VERSION 5.7 ;
  NOWIREEXTENSIONATPIN ON ;
  DIVIDERCHAR "/" ;
  BUSBITCHARS "[]" ;
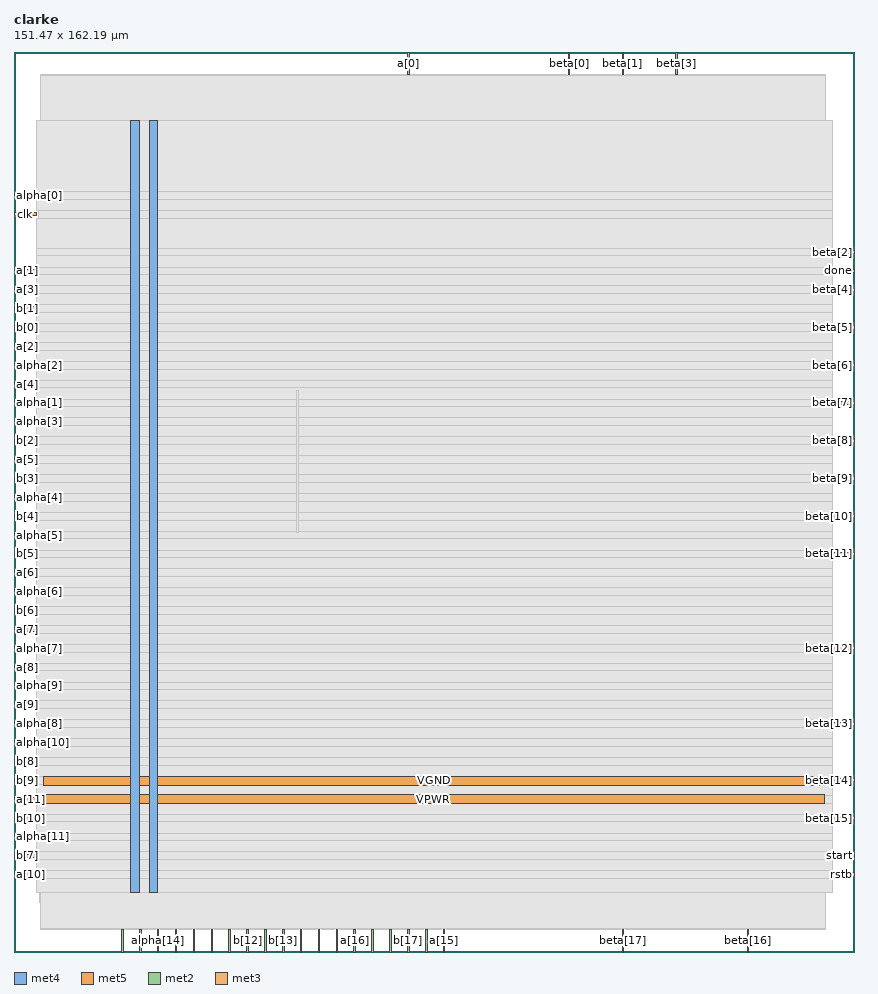
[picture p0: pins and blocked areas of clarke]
MACRO clarke
  CLASS BLOCK ;
  FOREIGN clarke ;
  ORIGIN 0.000 0.000 ;
  SIZE 151.470 BY 162.190 ;
  PIN VGND
    DIRECTION INOUT ;
    USE GROUND ;
    PORT
      LAYER met4 ;
        RECT 24.340 10.640 25.940 149.840 ;
    END
    PORT
      LAYER met5 ;
        RECT 5.280 30.030 146.060 31.630 ;
    END
  END VGND
  PIN VPWR
    DIRECTION INOUT ;
    USE POWER ;
    PORT
      LAYER met4 ;
        RECT 21.040 10.640 22.640 149.840 ;
    END
    PORT
      LAYER met5 ;
        RECT 5.280 26.730 146.060 28.330 ;
    END
  END VPWR
  PIN a[0]
    DIRECTION INPUT ;
    USE SIGNAL ;
    ANTENNAGATEAREA 0.126000 ;
    PORT
      LAYER met2 ;
        RECT 70.930 158.190 71.210 162.190 ;
    END
  END a[0]
  PIN a[10]
    DIRECTION INPUT ;
    USE SIGNAL ;
    ANTENNAGATEAREA 0.196500 ;
    PORT
      LAYER met3 ;
        RECT 0.000 13.640 4.000 14.240 ;
    END
  END a[10]
  PIN a[11]
    DIRECTION INPUT ;
    USE SIGNAL ;
    ANTENNAGATEAREA 0.196500 ;
    PORT
      LAYER met3 ;
        RECT 0.000 27.240 4.000 27.840 ;
    END
  END a[11]
  PIN a[12]
    DIRECTION INPUT ;
    USE SIGNAL ;
    ANTENNAGATEAREA 0.196500 ;
    PORT
      LAYER met2 ;
        RECT 19.410 0.000 19.690 4.000 ;
    END
  END a[12]
  PIN a[13]
    DIRECTION INPUT ;
    USE SIGNAL ;
    ANTENNAGATEAREA 0.196500 ;
    PORT
      LAYER met2 ;
        RECT 32.290 0.000 32.570 4.000 ;
    END
  END a[13]
  PIN a[14]
    DIRECTION INPUT ;
    USE SIGNAL ;
    ANTENNAGATEAREA 0.196500 ;
    PORT
      LAYER met2 ;
        RECT 22.630 0.000 22.910 4.000 ;
    END
  END a[14]
  PIN a[15]
    DIRECTION INPUT ;
    USE SIGNAL ;
    ANTENNAGATEAREA 0.196500 ;
    PORT
      LAYER met2 ;
        RECT 77.370 0.000 77.650 4.000 ;
    END
  END a[15]
  PIN a[16]
    DIRECTION INPUT ;
    USE SIGNAL ;
    ANTENNAGATEAREA 0.196500 ;
    PORT
      LAYER met2 ;
        RECT 61.270 0.000 61.550 4.000 ;
    END
  END a[16]
  PIN a[17]
    DIRECTION INPUT ;
    USE SIGNAL ;
    ANTENNAGATEAREA 0.213000 ;
    PORT
      LAYER met2 ;
        RECT 74.150 0.000 74.430 4.000 ;
    END
  END a[17]
  PIN a[1]
    DIRECTION INPUT ;
    USE SIGNAL ;
    ANTENNAGATEAREA 0.196500 ;
    PORT
      LAYER met3 ;
        RECT 0.000 122.440 4.000 123.040 ;
    END
  END a[1]
  PIN a[2]
    DIRECTION INPUT ;
    USE SIGNAL ;
    ANTENNAGATEAREA 0.495000 ;
    PORT
      LAYER met3 ;
        RECT 0.000 108.840 4.000 109.440 ;
    END
  END a[2]
  PIN a[3]
    DIRECTION INPUT ;
    USE SIGNAL ;
    ANTENNAGATEAREA 0.196500 ;
    PORT
      LAYER met3 ;
        RECT 0.000 119.040 4.000 119.640 ;
    END
  END a[3]
  PIN a[4]
    DIRECTION INPUT ;
    USE SIGNAL ;
    ANTENNAGATEAREA 0.196500 ;
    PORT
      LAYER met3 ;
        RECT 0.000 102.040 4.000 102.640 ;
    END
  END a[4]
  PIN a[5]
    DIRECTION INPUT ;
    USE SIGNAL ;
    ANTENNAGATEAREA 0.196500 ;
    PORT
      LAYER met3 ;
        RECT 0.000 88.440 4.000 89.040 ;
    END
  END a[5]
  PIN a[6]
    DIRECTION INPUT ;
    USE SIGNAL ;
    ANTENNAGATEAREA 0.196500 ;
    PORT
      LAYER met3 ;
        RECT 0.000 68.040 4.000 68.640 ;
    END
  END a[6]
  PIN a[7]
    DIRECTION INPUT ;
    USE SIGNAL ;
    ANTENNAGATEAREA 0.196500 ;
    PORT
      LAYER met3 ;
        RECT 0.000 57.840 4.000 58.440 ;
    END
  END a[7]
  PIN a[8]
    DIRECTION INPUT ;
    USE SIGNAL ;
    ANTENNAGATEAREA 0.196500 ;
    PORT
      LAYER met3 ;
        RECT 0.000 51.040 4.000 51.640 ;
    END
  END a[8]
  PIN a[9]
    DIRECTION INPUT ;
    USE SIGNAL ;
    ANTENNAGATEAREA 0.196500 ;
    PORT
      LAYER met3 ;
        RECT 0.000 44.240 4.000 44.840 ;
    END
  END a[9]
  PIN alpha[0]
    DIRECTION OUTPUT ;
    USE SIGNAL ;
    ANTENNADIFFAREA 0.795200 ;
    PORT
      LAYER met3 ;
        RECT 0.000 136.040 4.000 136.640 ;
    END
  END alpha[0]
  PIN alpha[10]
    DIRECTION OUTPUT ;
    USE SIGNAL ;
    ANTENNADIFFAREA 0.795200 ;
    PORT
      LAYER met3 ;
        RECT 0.000 37.440 4.000 38.040 ;
    END
  END alpha[10]
  PIN alpha[11]
    DIRECTION OUTPUT ;
    USE SIGNAL ;
    ANTENNADIFFAREA 0.795200 ;
    PORT
      LAYER met3 ;
        RECT 0.000 20.440 4.000 21.040 ;
    END
  END alpha[11]
  PIN alpha[12]
    DIRECTION OUTPUT ;
    USE SIGNAL ;
    ANTENNADIFFAREA 0.795200 ;
    PORT
      LAYER met2 ;
        RECT 29.070 0.000 29.350 4.000 ;
    END
  END alpha[12]
  PIN alpha[13]
    DIRECTION OUTPUT ;
    USE SIGNAL ;
    ANTENNADIFFAREA 0.795200 ;
    PORT
      LAYER met2 ;
        RECT 35.510 0.000 35.790 4.000 ;
    END
  END alpha[13]
  PIN alpha[14]
    DIRECTION OUTPUT ;
    USE SIGNAL ;
    ANTENNADIFFAREA 0.795200 ;
    PORT
      LAYER met2 ;
        RECT 25.850 0.000 26.130 4.000 ;
    END
  END alpha[14]
  PIN alpha[15]
    DIRECTION OUTPUT ;
    USE SIGNAL ;
    ANTENNADIFFAREA 0.795200 ;
    PORT
      LAYER met2 ;
        RECT 45.170 0.000 45.450 4.000 ;
    END
  END alpha[15]
  PIN alpha[16]
    DIRECTION OUTPUT ;
    USE SIGNAL ;
    ANTENNADIFFAREA 0.795200 ;
    PORT
      LAYER met2 ;
        RECT 54.830 0.000 55.110 4.000 ;
    END
  END alpha[16]
  PIN alpha[17]
    DIRECTION OUTPUT ;
    USE SIGNAL ;
    ANTENNADIFFAREA 0.795200 ;
    PORT
      LAYER met2 ;
        RECT 64.490 0.000 64.770 4.000 ;
    END
  END alpha[17]
  PIN alpha[1]
    DIRECTION OUTPUT ;
    USE SIGNAL ;
    ANTENNADIFFAREA 0.795200 ;
    PORT
      LAYER met3 ;
        RECT 0.000 98.640 4.000 99.240 ;
    END
  END alpha[1]
  PIN alpha[2]
    DIRECTION OUTPUT ;
    USE SIGNAL ;
    ANTENNADIFFAREA 0.795200 ;
    PORT
      LAYER met3 ;
        RECT 0.000 105.440 4.000 106.040 ;
    END
  END alpha[2]
  PIN alpha[3]
    DIRECTION OUTPUT ;
    USE SIGNAL ;
    ANTENNADIFFAREA 0.795200 ;
    PORT
      LAYER met3 ;
        RECT 0.000 95.240 4.000 95.840 ;
    END
  END alpha[3]
  PIN alpha[4]
    DIRECTION OUTPUT ;
    USE SIGNAL ;
    ANTENNADIFFAREA 0.795200 ;
    PORT
      LAYER met3 ;
        RECT 0.000 81.640 4.000 82.240 ;
    END
  END alpha[4]
  PIN alpha[5]
    DIRECTION OUTPUT ;
    USE SIGNAL ;
    ANTENNADIFFAREA 0.795200 ;
    PORT
      LAYER met3 ;
        RECT 0.000 74.840 4.000 75.440 ;
    END
  END alpha[5]
  PIN alpha[6]
    DIRECTION OUTPUT ;
    USE SIGNAL ;
    ANTENNADIFFAREA 0.795200 ;
    PORT
      LAYER met3 ;
        RECT 0.000 64.640 4.000 65.240 ;
    END
  END alpha[6]
  PIN alpha[7]
    DIRECTION OUTPUT ;
    USE SIGNAL ;
    ANTENNADIFFAREA 0.795200 ;
    PORT
      LAYER met3 ;
        RECT 0.000 54.440 4.000 55.040 ;
    END
  END alpha[7]
  PIN alpha[8]
    DIRECTION OUTPUT ;
    USE SIGNAL ;
    ANTENNADIFFAREA 0.795200 ;
    PORT
      LAYER met3 ;
        RECT 0.000 40.840 4.000 41.440 ;
    END
  END alpha[8]
  PIN alpha[9]
    DIRECTION OUTPUT ;
    USE SIGNAL ;
    ANTENNADIFFAREA 0.795200 ;
    PORT
      LAYER met3 ;
        RECT 0.000 47.640 4.000 48.240 ;
    END
  END alpha[9]
  PIN b[0]
    DIRECTION INPUT ;
    USE SIGNAL ;
    ANTENNAGATEAREA 0.196500 ;
    PORT
      LAYER met3 ;
        RECT 0.000 112.240 4.000 112.840 ;
    END
  END b[0]
  PIN b[10]
    DIRECTION INPUT ;
    USE SIGNAL ;
    ANTENNAGATEAREA 0.196500 ;
    PORT
      LAYER met3 ;
        RECT 0.000 23.840 4.000 24.440 ;
    END
  END b[10]
  PIN b[11]
    DIRECTION INPUT ;
    USE SIGNAL ;
    ANTENNAGATEAREA 0.196500 ;
    PORT
      LAYER met2 ;
        RECT 38.730 0.000 39.010 4.000 ;
    END
  END b[11]
  PIN b[12]
    DIRECTION INPUT ;
    USE SIGNAL ;
    ANTENNAGATEAREA 0.196500 ;
    PORT
      LAYER met2 ;
        RECT 41.950 0.000 42.230 4.000 ;
    END
  END b[12]
  PIN b[13]
    DIRECTION INPUT ;
    USE SIGNAL ;
    ANTENNAGATEAREA 0.196500 ;
    PORT
      LAYER met2 ;
        RECT 48.390 0.000 48.670 4.000 ;
    END
  END b[13]
  PIN b[14]
    DIRECTION INPUT ;
    USE SIGNAL ;
    ANTENNAGATEAREA 0.196500 ;
    PORT
      LAYER met2 ;
        RECT 51.610 0.000 51.890 4.000 ;
    END
  END b[14]
  PIN b[15]
    DIRECTION INPUT ;
    USE SIGNAL ;
    ANTENNAGATEAREA 0.196500 ;
    PORT
      LAYER met2 ;
        RECT 58.050 0.000 58.330 4.000 ;
    END
  END b[15]
  PIN b[16]
    DIRECTION INPUT ;
    USE SIGNAL ;
    ANTENNAGATEAREA 0.196500 ;
    PORT
      LAYER met2 ;
        RECT 67.710 0.000 67.990 4.000 ;
    END
  END b[16]
  PIN b[17]
    DIRECTION INPUT ;
    USE SIGNAL ;
    ANTENNAGATEAREA 0.196500 ;
    PORT
      LAYER met2 ;
        RECT 70.930 0.000 71.210 4.000 ;
    END
  END b[17]
  PIN b[1]
    DIRECTION INPUT ;
    USE SIGNAL ;
    ANTENNAGATEAREA 0.495000 ;
    PORT
      LAYER met3 ;
        RECT 0.000 115.640 4.000 116.240 ;
    END
  END b[1]
  PIN b[2]
    DIRECTION INPUT ;
    USE SIGNAL ;
    ANTENNAGATEAREA 0.196500 ;
    PORT
      LAYER met3 ;
        RECT 0.000 91.840 4.000 92.440 ;
    END
  END b[2]
  PIN b[3]
    DIRECTION INPUT ;
    USE SIGNAL ;
    ANTENNAGATEAREA 0.196500 ;
    PORT
      LAYER met3 ;
        RECT 0.000 85.040 4.000 85.640 ;
    END
  END b[3]
  PIN b[4]
    DIRECTION INPUT ;
    USE SIGNAL ;
    ANTENNAGATEAREA 0.196500 ;
    PORT
      LAYER met3 ;
        RECT 0.000 78.240 4.000 78.840 ;
    END
  END b[4]
  PIN b[5]
    DIRECTION INPUT ;
    USE SIGNAL ;
    ANTENNAGATEAREA 0.196500 ;
    PORT
      LAYER met3 ;
        RECT 0.000 71.440 4.000 72.040 ;
    END
  END b[5]
  PIN b[6]
    DIRECTION INPUT ;
    USE SIGNAL ;
    ANTENNAGATEAREA 0.196500 ;
    PORT
      LAYER met3 ;
        RECT 0.000 61.240 4.000 61.840 ;
    END
  END b[6]
  PIN b[7]
    DIRECTION INPUT ;
    USE SIGNAL ;
    ANTENNAGATEAREA 0.196500 ;
    PORT
      LAYER met3 ;
        RECT 0.000 17.040 4.000 17.640 ;
    END
  END b[7]
  PIN b[8]
    DIRECTION INPUT ;
    USE SIGNAL ;
    ANTENNAGATEAREA 0.196500 ;
    PORT
      LAYER met3 ;
        RECT 0.000 34.040 4.000 34.640 ;
    END
  END b[8]
  PIN b[9]
    DIRECTION INPUT ;
    USE SIGNAL ;
    ANTENNAGATEAREA 0.196500 ;
    PORT
      LAYER met3 ;
        RECT 0.000 30.640 4.000 31.240 ;
    END
  END b[9]
  PIN beta[0]
    DIRECTION OUTPUT ;
    USE SIGNAL ;
    ANTENNADIFFAREA 0.795200 ;
    PORT
      LAYER met2 ;
        RECT 99.910 158.190 100.190 162.190 ;
    END
  END beta[0]
  PIN beta[10]
    DIRECTION OUTPUT ;
    USE SIGNAL ;
    ANTENNADIFFAREA 0.445500 ;
    PORT
      LAYER met3 ;
        RECT 147.470 78.240 151.470 78.840 ;
    END
  END beta[10]
  PIN beta[11]
    DIRECTION OUTPUT ;
    USE SIGNAL ;
    ANTENNADIFFAREA 0.795200 ;
    PORT
      LAYER met3 ;
        RECT 147.470 71.440 151.470 72.040 ;
    END
  END beta[11]
  PIN beta[12]
    DIRECTION OUTPUT ;
    USE SIGNAL ;
    ANTENNADIFFAREA 0.795200 ;
    PORT
      LAYER met3 ;
        RECT 147.470 54.440 151.470 55.040 ;
    END
  END beta[12]
  PIN beta[13]
    DIRECTION OUTPUT ;
    USE SIGNAL ;
    ANTENNADIFFAREA 0.445500 ;
    PORT
      LAYER met3 ;
        RECT 147.470 40.840 151.470 41.440 ;
    END
  END beta[13]
  PIN beta[14]
    DIRECTION OUTPUT ;
    USE SIGNAL ;
    ANTENNADIFFAREA 0.445500 ;
    PORT
      LAYER met3 ;
        RECT 147.470 30.640 151.470 31.240 ;
    END
  END beta[14]
  PIN beta[15]
    DIRECTION OUTPUT ;
    USE SIGNAL ;
    ANTENNADIFFAREA 0.445500 ;
    PORT
      LAYER met3 ;
        RECT 147.470 23.840 151.470 24.440 ;
    END
  END beta[15]
  PIN beta[16]
    DIRECTION OUTPUT ;
    USE SIGNAL ;
    ANTENNADIFFAREA 0.795200 ;
    PORT
      LAYER met2 ;
        RECT 132.110 0.000 132.390 4.000 ;
    END
  END beta[16]
  PIN beta[17]
    DIRECTION OUTPUT ;
    USE SIGNAL ;
    ANTENNADIFFAREA 0.795200 ;
    PORT
      LAYER met2 ;
        RECT 109.570 0.000 109.850 4.000 ;
    END
  END beta[17]
  PIN beta[1]
    DIRECTION OUTPUT ;
    USE SIGNAL ;
    ANTENNADIFFAREA 0.795200 ;
    PORT
      LAYER met2 ;
        RECT 109.570 158.190 109.850 162.190 ;
    END
  END beta[1]
  PIN beta[2]
    DIRECTION OUTPUT ;
    USE SIGNAL ;
    ANTENNADIFFAREA 0.445500 ;
    PORT
      LAYER met3 ;
        RECT 147.470 125.840 151.470 126.440 ;
    END
  END beta[2]
  PIN beta[3]
    DIRECTION OUTPUT ;
    USE SIGNAL ;
    ANTENNADIFFAREA 0.795200 ;
    PORT
      LAYER met2 ;
        RECT 119.230 158.190 119.510 162.190 ;
    END
  END beta[3]
  PIN beta[4]
    DIRECTION OUTPUT ;
    USE SIGNAL ;
    ANTENNADIFFAREA 0.795200 ;
    PORT
      LAYER met3 ;
        RECT 147.470 119.040 151.470 119.640 ;
    END
  END beta[4]
  PIN beta[5]
    DIRECTION OUTPUT ;
    USE SIGNAL ;
    ANTENNADIFFAREA 0.445500 ;
    PORT
      LAYER met3 ;
        RECT 147.470 112.240 151.470 112.840 ;
    END
  END beta[5]
  PIN beta[6]
    DIRECTION OUTPUT ;
    USE SIGNAL ;
    ANTENNADIFFAREA 0.445500 ;
    PORT
      LAYER met3 ;
        RECT 147.470 105.440 151.470 106.040 ;
    END
  END beta[6]
  PIN beta[7]
    DIRECTION OUTPUT ;
    USE SIGNAL ;
    ANTENNADIFFAREA 0.795200 ;
    PORT
      LAYER met3 ;
        RECT 147.470 98.640 151.470 99.240 ;
    END
  END beta[7]
  PIN beta[8]
    DIRECTION OUTPUT ;
    USE SIGNAL ;
    ANTENNADIFFAREA 0.445500 ;
    PORT
      LAYER met3 ;
        RECT 147.470 91.840 151.470 92.440 ;
    END
  END beta[8]
  PIN beta[9]
    DIRECTION OUTPUT ;
    USE SIGNAL ;
    ANTENNADIFFAREA 0.795200 ;
    PORT
      LAYER met3 ;
        RECT 147.470 85.040 151.470 85.640 ;
    END
  END beta[9]
  PIN clk
    DIRECTION INPUT ;
    USE SIGNAL ;
    ANTENNAGATEAREA 0.852000 ;
    PORT
      LAYER met3 ;
        RECT 0.000 132.640 4.000 133.240 ;
    END
  END clk
  PIN done
    DIRECTION OUTPUT ;
    USE SIGNAL ;
    ANTENNADIFFAREA 0.795200 ;
    PORT
      LAYER met3 ;
        RECT 147.470 122.440 151.470 123.040 ;
    END
  END done
  PIN rstb
    DIRECTION INPUT ;
    USE SIGNAL ;
    ANTENNAGATEAREA 0.196500 ;
    PORT
      LAYER met3 ;
        RECT 147.470 13.640 151.470 14.240 ;
    END
  END rstb
  PIN start
    DIRECTION INPUT ;
    USE SIGNAL ;
    ANTENNAGATEAREA 0.196500 ;
    PORT
      LAYER met3 ;
        RECT 147.470 17.040 151.470 17.640 ;
    END
  END start
  OBS
      LAYER li1 ;
        RECT 5.520 10.795 145.820 149.685 ;
      LAYER met1 ;
        RECT 4.670 8.880 146.210 149.840 ;
      LAYER met2 ;
        RECT 4.690 157.910 70.650 158.190 ;
        RECT 71.490 157.910 99.630 158.190 ;
        RECT 100.470 157.910 109.290 158.190 ;
        RECT 110.130 157.910 118.950 158.190 ;
        RECT 119.790 157.910 146.190 158.190 ;
        RECT 4.690 4.280 146.190 157.910 ;
        RECT 4.690 4.000 19.130 4.280 ;
        RECT 19.970 4.000 22.350 4.280 ;
        RECT 23.190 4.000 25.570 4.280 ;
        RECT 26.410 4.000 28.790 4.280 ;
        RECT 29.630 4.000 32.010 4.280 ;
        RECT 32.850 4.000 35.230 4.280 ;
        RECT 36.070 4.000 38.450 4.280 ;
        RECT 39.290 4.000 41.670 4.280 ;
        RECT 42.510 4.000 44.890 4.280 ;
        RECT 45.730 4.000 48.110 4.280 ;
        RECT 48.950 4.000 51.330 4.280 ;
        RECT 52.170 4.000 54.550 4.280 ;
        RECT 55.390 4.000 57.770 4.280 ;
        RECT 58.610 4.000 60.990 4.280 ;
        RECT 61.830 4.000 64.210 4.280 ;
        RECT 65.050 4.000 67.430 4.280 ;
        RECT 68.270 4.000 70.650 4.280 ;
        RECT 71.490 4.000 73.870 4.280 ;
        RECT 74.710 4.000 77.090 4.280 ;
        RECT 77.930 4.000 109.290 4.280 ;
        RECT 110.130 4.000 131.830 4.280 ;
        RECT 132.670 4.000 146.190 4.280 ;
      LAYER met3 ;
        RECT 3.990 137.040 147.470 149.765 ;
        RECT 4.400 135.640 147.470 137.040 ;
        RECT 3.990 133.640 147.470 135.640 ;
        RECT 4.400 132.240 147.470 133.640 ;
        RECT 3.990 126.840 147.470 132.240 ;
        RECT 3.990 125.440 147.070 126.840 ;
        RECT 3.990 123.440 147.470 125.440 ;
        RECT 4.400 122.040 147.070 123.440 ;
        RECT 3.990 120.040 147.470 122.040 ;
        RECT 4.400 118.640 147.070 120.040 ;
        RECT 3.990 116.640 147.470 118.640 ;
        RECT 4.400 115.240 147.470 116.640 ;
        RECT 3.990 113.240 147.470 115.240 ;
        RECT 4.400 111.840 147.070 113.240 ;
        RECT 3.990 109.840 147.470 111.840 ;
        RECT 4.400 108.440 147.470 109.840 ;
        RECT 3.990 106.440 147.470 108.440 ;
        RECT 4.400 105.040 147.070 106.440 ;
        RECT 3.990 103.040 147.470 105.040 ;
        RECT 4.400 101.640 147.470 103.040 ;
        RECT 3.990 99.640 147.470 101.640 ;
        RECT 4.400 98.240 147.070 99.640 ;
        RECT 3.990 96.240 147.470 98.240 ;
        RECT 4.400 94.840 147.470 96.240 ;
        RECT 3.990 92.840 147.470 94.840 ;
        RECT 4.400 91.440 147.070 92.840 ;
        RECT 3.990 89.440 147.470 91.440 ;
        RECT 4.400 88.040 147.470 89.440 ;
        RECT 3.990 86.040 147.470 88.040 ;
        RECT 4.400 84.640 147.070 86.040 ;
        RECT 3.990 82.640 147.470 84.640 ;
        RECT 4.400 81.240 147.470 82.640 ;
        RECT 3.990 79.240 147.470 81.240 ;
        RECT 4.400 77.840 147.070 79.240 ;
        RECT 3.990 75.840 147.470 77.840 ;
        RECT 4.400 74.440 147.470 75.840 ;
        RECT 3.990 72.440 147.470 74.440 ;
        RECT 4.400 71.040 147.070 72.440 ;
        RECT 3.990 69.040 147.470 71.040 ;
        RECT 4.400 67.640 147.470 69.040 ;
        RECT 3.990 65.640 147.470 67.640 ;
        RECT 4.400 64.240 147.470 65.640 ;
        RECT 3.990 62.240 147.470 64.240 ;
        RECT 4.400 60.840 147.470 62.240 ;
        RECT 3.990 58.840 147.470 60.840 ;
        RECT 4.400 57.440 147.470 58.840 ;
        RECT 3.990 55.440 147.470 57.440 ;
        RECT 4.400 54.040 147.070 55.440 ;
        RECT 3.990 52.040 147.470 54.040 ;
        RECT 4.400 50.640 147.470 52.040 ;
        RECT 3.990 48.640 147.470 50.640 ;
        RECT 4.400 47.240 147.470 48.640 ;
        RECT 3.990 45.240 147.470 47.240 ;
        RECT 4.400 43.840 147.470 45.240 ;
        RECT 3.990 41.840 147.470 43.840 ;
        RECT 4.400 40.440 147.070 41.840 ;
        RECT 3.990 38.440 147.470 40.440 ;
        RECT 4.400 37.040 147.470 38.440 ;
        RECT 3.990 35.040 147.470 37.040 ;
        RECT 4.400 33.640 147.470 35.040 ;
        RECT 3.990 31.640 147.470 33.640 ;
        RECT 4.400 30.240 147.070 31.640 ;
        RECT 3.990 28.240 147.470 30.240 ;
        RECT 4.400 26.840 147.470 28.240 ;
        RECT 3.990 24.840 147.470 26.840 ;
        RECT 4.400 23.440 147.070 24.840 ;
        RECT 3.990 21.440 147.470 23.440 ;
        RECT 4.400 20.040 147.470 21.440 ;
        RECT 3.990 18.040 147.470 20.040 ;
        RECT 4.400 16.640 147.070 18.040 ;
        RECT 3.990 14.640 147.470 16.640 ;
        RECT 4.400 13.240 147.070 14.640 ;
        RECT 3.990 10.715 147.470 13.240 ;
      LAYER met4 ;
        RECT 50.895 75.655 51.225 101.145 ;
  END
END clarke
END LIBRARY

